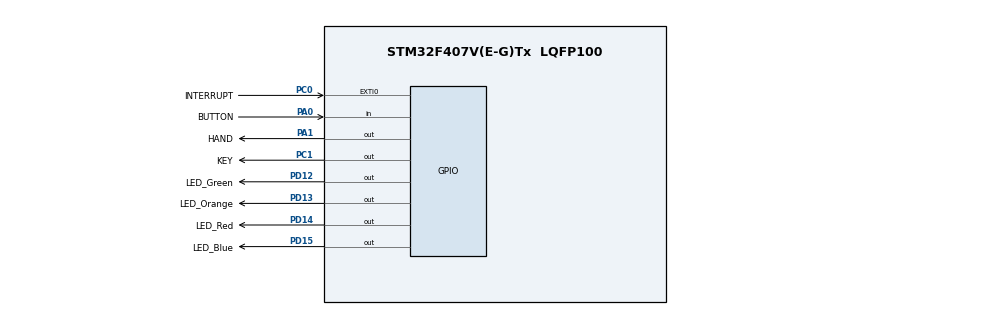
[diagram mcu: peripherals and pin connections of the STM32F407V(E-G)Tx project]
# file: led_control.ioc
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Mcu.Family=STM32F4
Mcu.Name=STM32F407V(E-G)Tx
Mcu.Package=LQFP100
NVIC.EXTI0_IRQn=true\:0\:0\:false\:false\:true\:true\:true\:true
NVIC.PriorityGroup=NVIC_PRIORITYGROUP_4
PA0-WKUP.GPIO_Label=BUTTON
PA0-WKUP.Signal=GPIO_Input
PA1.GPIO_Label=HAND
PA1.GPIO_PuPd=GPIO_PULLDOWN
PA1.Signal=GPIO_Output
PA13.Mode=Serial_Wire
PA13.Signal=SYS_JTMS-SWDIO
PA14.Mode=Serial_Wire
PA14.Signal=SYS_JTCK-SWCLK
PC0.GPIO_Label=INTERRUPT
PC0.GPIO_PuPd=GPIO_PULLDOWN
PC0.Signal=GPXTI0
PC1.GPIO_Label=KEY
PC1.GPIO_PuPd=GPIO_PULLDOWN
PC1.Signal=GPIO_Output
PD12.GPIO_Label=LED_Green
PD12.GPIO_PuPd=GPIO_PULLDOWN
PD12.Signal=GPIO_Output
PD13.GPIO_Label=LED_Orange
PD13.GPIO_PuPd=GPIO_PULLDOWN
PD13.Signal=GPIO_Output
PD14.GPIO_Label=LED_Red
PD14.GPIO_PuPd=GPIO_PULLDOWN
PD14.Signal=GPIO_Output
PD15.GPIO_Label=LED_Blue
PD15.GPIO_PuPd=GPIO_PULLDOWN
PD15.Signal=GPIO_Output
PH0-OSC_IN.Mode=HSE-External-Oscillator
PH0-OSC_IN.Signal=RCC_OSC_IN
PH1-OSC_OUT.Mode=HSE-External-Oscillator
PH1-OSC_OUT.Signal=RCC_OSC_OUT
ProjectManager.HeapSize=0x200
ProjectManager.StackSize=0x400
ProjectManager.TargetToolchain=MDK-ARM V5.32
RCC.48MHZClocksFreq_Value=42000000
RCC.AHBFreq_Value=8000000
RCC.APB1CLKDivider=RCC_HCLK_DIV4
RCC.APB1Freq_Value=2000000
RCC.APB1TimFreq_Value=4000000
RCC.APB2CLKDivider=RCC_HCLK_DIV2
RCC.APB2Freq_Value=4000000
RCC.APB2TimFreq_Value=8000000
RCC.CortexFreq_Value=8000000
RCC.HCLKFreq_Value=8000000
RCC.HSE_VALUE=8000000
RCC.HSI_VALUE=16000000
RCC.LSE_VALUE=32768
RCC.PLLM=8
RCC.PLLN=168
RCC.PLLSourceVirtual=RCC_PLLSOURCE_HSE
RCC.SYSCLKFreq_VALUE=8000000
RCC.SYSCLKSource=RCC_SYSCLKSOURCE_HSE
RCC.VCOOutputFreq_Value=168000000
board=custom

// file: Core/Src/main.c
/* USER CODE BEGIN Header */
/**
  ******************************************************************************
  * @file           : main.c
  * @brief          : Main program body
  ******************************************************************************
  * @attention
  *
  * Copyright (c) 2024 STMicroelectronics.
  * All rights reserved.
  *
  * This software is licensed under terms that can be found in the LICENSE file
  * in the root directory of this software component.
  * If no LICENSE file comes with this software, it is provided AS-IS.
  *
  ******************************************************************************
  */
/* USER CODE END Header */
#include "main.h"
#include "gpio.h"

/* USER CODE BEGIN PTD */

typedef enum
{
	FORWARD = 0,
	REVERSE = 1,
}direction_e_t;

/* USER CODE END PTD */

/* USER CODE BEGIN PD */
#define second 1000
#define LED_GPIO_Port LED_Green_GPIO_Port //same port
//#define NUM_LEDS (sizeof(LEDs) / sizeof(LED_TypeDef)) // Array size
/* USER CODE END PD */

/* USER CODE BEGIN PV */

static GPIO_PinState pin_state = GPIO_PIN_RESET;

//static bool flag_set_button = false;

static leds_color_e_t led_switcher = GREEN;
static direction_e_t direction = FORWARD;
static uint32_t timeout = 0;
static uint16_t leds[ALL] = {LED_Green_Pin, LED_Orange_Pin, LED_Red_Pin, LED_Blue_Pin};

// Initialization of the array with LEDs
//	   LED_TypeDef LEDs[] = {
//    {LED_Blue_GPIO_Port, LED_Blue_Pin},
//    {LED_Red_GPIO_Port, LED_Red_Pin},
//    {LED_Orange_GPIO_Port, LED_Orange_Pin},
//    {LED_Green_GPIO_Port, LED_Green_Pin}
//    };
//
//		uint8_t current_led = 0; // Variable for tracking the current LED
/* USER CODE END PV */

void SystemClock_Config(void);

/* USER CODE BEGIN 0 */

// Function to turn off all LEDs
//void TurnOffAllLEDs(void) {
//    for (uint8_t i = 0; i < NUM_LEDS; i++) {
//        HAL_GPIO_WritePin(LEDs[i].Port, LEDs[i].Pin, GPIO_PIN_RESET);
//    }
//}

//// Function for switching to the next LED
//void Next_LED(void) {
//    // Turn off all LEDs
//    TurnOffAllLEDs();
//
//    // Turn on the next LED
//    HAL_GPIO_WritePin(LEDs[current_led].Port, LEDs[current_led].Pin, GPIO_PIN_SET);
//
//    // Increase the counter
//    current_led++;

//    // If the counter has reached the end of the array, reset it to 0
//    if (current_led >= NUM_LEDS) {
//        current_led = 0;
//    }
//}
/* USER CODE END 0 */

int main(void)
{

  /* USER CODE BEGIN 1 */
   GPIO_PinState pin_state = GPIO_PIN_RESET;

  /* USER CODE END 1 */

  /* MCU Configuration--------------------------------------------------------*/

  /* Reset of all peripherals, Initializes the Flash interface and the Systick. */
  HAL_Init();

  /* Configure the system clock */
  SystemClock_Config();

  /* Initialize all configured peripherals */
  MX_GPIO_Init();
  /* USER CODE BEGIN 2 */
  // HAL_GPIO_WritePin(LED_Red_GPIO_Port, LED_Red_Pin, GPIO_PIN_SET);

	//for (uint32_t i; i < ALL; i++)
	HAL_GPIO_WritePin(LED_GPIO_Port, leds[led_switcher], GPIO_PIN_SET);
	timeout = 250;
  /* USER CODE END 2 */

  /* Infinite loop */
  while (1)
  {

		HAL_Delay(timeout);

		HAL_GPIO_WritePin(LED_GPIO_Port, leds[led_switcher], GPIO_PIN_RESET);
    if(direction == FORWARD)
		{
		led_switcher ++;
		if (led_switcher == ALL)
		{
			led_switcher = GREEN;
		}
	}
		else
		{

		if (led_switcher == GREEN)
		{
			led_switcher = ALL;
		}
		led_switcher --;
		}
		HAL_GPIO_WritePin(LED_GPIO_Port, leds[led_switcher], GPIO_PIN_SET);

//		if (HAL_GPIO_ReadPin(BUTTON_GPIO_Port, BUTTON_Pin) == GPIO_PIN_SET) {      // If the button is pressed
//				HAL_Delay(50);
//				if (HAL_GPIO_ReadPin(BUTTON_GPIO_Port, BUTTON_Pin) == GPIO_PIN_SET) {  // If the button is still pressed
//
//						Next_LED();   // Switch to the next LED
//
//						while (HAL_GPIO_ReadPin(BUTTON_GPIO_Port, BUTTON_Pin) == GPIO_PIN_SET) { // Wait for the button to be released to avoid multiple triggering
//
//						}
//				}
//		}

  }
}

void SystemClock_Config(void)
{
  RCC_OscInitTypeDef RCC_OscInitStruct = {0};
  RCC_ClkInitTypeDef RCC_ClkInitStruct = {0};

  /** Configure the main internal regulator output voltage
  */
  __HAL_RCC_PWR_CLK_ENABLE();
  __HAL_PWR_VOLTAGESCALING_CONFIG(PWR_REGULATOR_VOLTAGE_SCALE1);

  /** Initializes the RCC Oscillators according to the specified parameters
  * in the RCC_OscInitTypeDef structure.
  */
  RCC_OscInitStruct.OscillatorType = RCC_OSCILLATORTYPE_HSE;
  RCC_OscInitStruct.HSEState = RCC_HSE_ON;
  RCC_OscInitStruct.PLL.PLLState = RCC_PLL_ON;
  RCC_OscInitStruct.PLL.PLLSource = RCC_PLLSOURCE_HSE;
  RCC_OscInitStruct.PLL.PLLM = 8;
  RCC_OscInitStruct.PLL.PLLN = 168;
  RCC_OscInitStruct.PLL.PLLP = RCC_PLLP_DIV2;
  RCC_OscInitStruct.PLL.PLLQ = 4;
  if (HAL_RCC_OscConfig(&RCC_OscInitStruct) != HAL_OK)
  {
    Error_Handler();
  }

  /** Initializes the CPU, AHB and APB buses clocks
  */
  RCC_ClkInitStruct.ClockType = RCC_CLOCKTYPE_HCLK|RCC_CLOCKTYPE_SYSCLK
                              |RCC_CLOCKTYPE_PCLK1|RCC_CLOCKTYPE_PCLK2;
  RCC_ClkInitStruct.SYSCLKSource = RCC_SYSCLKSOURCE_PLLCLK;
  RCC_ClkInitStruct.AHBCLKDivider = RCC_SYSCLK_DIV1;
  RCC_ClkInitStruct.APB1CLKDivider = RCC_HCLK_DIV4;
  RCC_ClkInitStruct.APB2CLKDivider = RCC_HCLK_DIV2;

  if (HAL_RCC_ClockConfig(&RCC_ClkInitStruct, FLASH_LATENCY_2) != HAL_OK)
  {
    Error_Handler();
  }

  /** Enables the Clock Security System
  */
  HAL_RCC_EnableCSS();
}

/* USER CODE BEGIN 4 */
void HAL_GPIO_EXTI_Callback(uint16_t GPIO_Pin)
{
if(direction == FORWARD)
{
	direction = REVERSE;
}
		else
		{
			direction = FORWARD;
		}
}

/* USER CODE END 4 */

void Error_Handler(void)
{
  __disable_irq();
  while (1)
  {
  }
}
